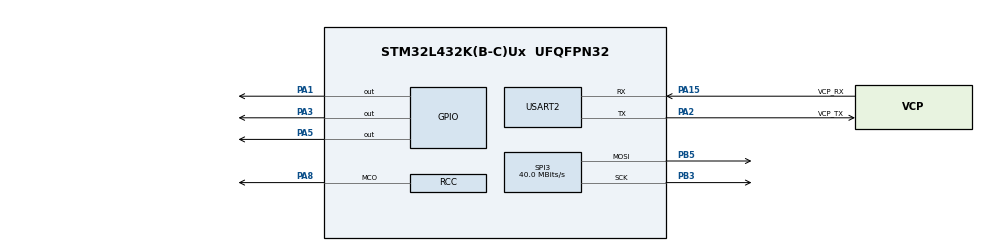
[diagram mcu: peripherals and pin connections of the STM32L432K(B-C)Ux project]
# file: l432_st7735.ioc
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Mcu.Family=STM32L4
Mcu.Name=STM32L432K(B-C)Ux
Mcu.Package=UFQFPN32
NVIC.PriorityGroup=NVIC_PRIORITYGROUP_4
PA0.GPIO_Label=MCO [High speed clock in]
PA0.Signal=RCC_CK_IN
PA1.Signal=GPIO_Output
PA13\ (JTMS-SWDIO).GPIO_Label=SWDIO
PA13\ (JTMS-SWDIO).Mode=Serial_Wire
PA13\ (JTMS-SWDIO).Signal=SYS_JTMS-SWDIO
PA14\ (JTCK-SWCLK).GPIO_Label=SWCLK
PA14\ (JTCK-SWCLK).Mode=Serial_Wire
PA14\ (JTCK-SWCLK).Signal=SYS_JTCK-SWCLK
PA15\ (JTDI).GPIO_Label=VCP_RX
PA15\ (JTDI).Mode=Asynchronous
PA15\ (JTDI).Signal=USART2_RX
PA2.GPIO_Label=VCP_TX
PA2.Mode=Asynchronous
PA2.Signal=USART2_TX
PA3.Signal=GPIO_Output
PA5.Signal=GPIO_Output
PA8.Mode=Clock-out
PA8.Signal=RCC_MCO
PB3\ (JTDO-TRACESWO).Mode=TX_Only_Simplex_Unidirect_Master
PB3\ (JTDO-TRACESWO).Signal=SPI3_SCK
PB5.Mode=TX_Only_Simplex_Unidirect_Master
PB5.Signal=SPI3_MOSI
PC14-OSC32_IN\ (PC14).Mode=LSE-External-Oscillator
PC14-OSC32_IN\ (PC14).Signal=RCC_OSC32_IN
PC15-OSC32_OUT\ (PC15).Mode=LSE-External-Oscillator
PC15-OSC32_OUT\ (PC15).Signal=RCC_OSC32_OUT
ProjectManager.HeapSize=0x200
ProjectManager.StackSize=0x400
ProjectManager.TargetToolchain=MDK-ARM V5.32
RCC.ADCFreq_Value=64000000
RCC.AHBFreq_Value=80000000
RCC.APB1Freq_Value=80000000
RCC.APB1TimFreq_Value=80000000
RCC.APB2Freq_Value=80000000
RCC.APB2TimFreq_Value=80000000
RCC.CortexFreq_Value=80000000
RCC.HCLKFreq_Value=80000000
RCC.HSE_VALUE=8000000
RCC.HSI16_VALUE=16000000
RCC.HSI48_VALUE=48000000
RCC.HSI_VALUE=16000000
RCC.MSI_VALUE=4000000
RCC.PLLMUL=RCC_PLLMUL_4
RCC.PLLN=10
RCC.PLLSourceVirtual=RCC_PLLSOURCE_HSI
RCC.PREFETCH_ENABLE=1
RCC.RCC_MCODiv=RCC_MCODIV_8
RCC.SYSCLKFreq_VALUE=80000000
RCC.SYSCLKSource=RCC_SYSCLKSOURCE_PLLCLK
RCC.USBFreq_Value=64000000
RCC.VCOOutputFreq_Value=160000000
SPI3.BaudRatePrescaler=SPI_BAUDRATEPRESCALER_2
SPI3.CalculateBaudRate=40.0 MBits/s
SPI3.DataSize=SPI_DATASIZE_8BIT
SPI3.Direction=SPI_DIRECTION_2LINES
SPI3.Mode=SPI_MODE_MASTER
SPI3.VirtualType=VM_MASTER
USART2.VirtualMode-Asynchronous=VM_ASYNC
board=NUCLEO-L432KC

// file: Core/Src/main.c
/* USER CODE BEGIN Header */
/**
  ******************************************************************************
  * @file           : main.c
  * @brief          : Main program body
  ******************************************************************************
  * @attention
  *
  * Copyright (c) 2021 STMicroelectronics.
  * All rights reserved.
  *
  * This software is licensed under terms that can be found in the LICENSE file
  * in the root directory of this software component.
  * If no LICENSE file comes with this software, it is provided AS-IS.
  *
  ******************************************************************************
  */
/* USER CODE END Header */
#include "main.h"

/* USER CODE BEGIN Includes */
#include "st7735.h"
#include "image.h"
/* USER CODE END Includes */

SPI_HandleTypeDef hspi3;

UART_HandleTypeDef huart2;

void SystemClock_Config(void);
static void MX_GPIO_Init(void);
static void MX_SPI3_Init(void);
static void MX_USART2_UART_Init(void);

int main(void)
{

  /* MCU Configuration--------------------------------------------------------*/

  /* Reset of all peripherals, Initializes the Flash interface and the Systick. */
  HAL_Init();

  /* Configure the system clock */
  SystemClock_Config();

  /* Initialize all configured peripherals */
  MX_GPIO_Init();
  MX_SPI3_Init();
  MX_USART2_UART_Init();
  /* USER CODE BEGIN 2 */

	//Change here

//  ST7735_init();
//
//	ST7735_Clr();
//
//	inhinhanh();

  /* USER CODE END 2 */

  /* Infinite loop */
  while (1)
  {

  }
}

void SystemClock_Config(void)
{
  RCC_OscInitTypeDef RCC_OscInitStruct = {0};
  RCC_ClkInitTypeDef RCC_ClkInitStruct = {0};

  /** Configure the main internal regulator output voltage
  */
  if (HAL_PWREx_ControlVoltageScaling(PWR_REGULATOR_VOLTAGE_SCALE1) != HAL_OK)
  {
    Error_Handler();
  }
  /** Initializes the RCC Oscillators according to the specified parameters
  * in the RCC_OscInitTypeDef structure.
  */
  RCC_OscInitStruct.OscillatorType = RCC_OSCILLATORTYPE_HSI;
  RCC_OscInitStruct.HSIState = RCC_HSI_ON;
  RCC_OscInitStruct.HSICalibrationValue = RCC_HSICALIBRATION_DEFAULT;
  RCC_OscInitStruct.PLL.PLLState = RCC_PLL_ON;
  RCC_OscInitStruct.PLL.PLLSource = RCC_PLLSOURCE_HSI;
  RCC_OscInitStruct.PLL.PLLM = 1;
  RCC_OscInitStruct.PLL.PLLN = 12;
  RCC_OscInitStruct.PLL.PLLP = RCC_PLLP_DIV7;
  RCC_OscInitStruct.PLL.PLLQ = RCC_PLLQ_DIV2;
  RCC_OscInitStruct.PLL.PLLR = RCC_PLLR_DIV8;
  if (HAL_RCC_OscConfig(&RCC_OscInitStruct) != HAL_OK)
  {
    Error_Handler();
  }
  /** Initializes the CPU, AHB and APB buses clocks
  */
  RCC_ClkInitStruct.ClockType = RCC_CLOCKTYPE_HCLK|RCC_CLOCKTYPE_SYSCLK
                              |RCC_CLOCKTYPE_PCLK1|RCC_CLOCKTYPE_PCLK2;
  RCC_ClkInitStruct.SYSCLKSource = RCC_SYSCLKSOURCE_PLLCLK;
  RCC_ClkInitStruct.AHBCLKDivider = RCC_SYSCLK_DIV1;
  RCC_ClkInitStruct.APB1CLKDivider = RCC_HCLK_DIV1;
  RCC_ClkInitStruct.APB2CLKDivider = RCC_HCLK_DIV1;

  if (HAL_RCC_ClockConfig(&RCC_ClkInitStruct, FLASH_LATENCY_1) != HAL_OK)
  {
    Error_Handler();
  }
}

static void MX_SPI3_Init(void)
{

  /* SPI3 parameter configuration*/
  hspi3.Instance = SPI3;
  hspi3.Init.Mode = SPI_MODE_MASTER;
  hspi3.Init.Direction = SPI_DIRECTION_2LINES;
  hspi3.Init.DataSize = SPI_DATASIZE_8BIT;
  hspi3.Init.CLKPolarity = SPI_POLARITY_LOW;
  hspi3.Init.CLKPhase = SPI_PHASE_1EDGE;
  hspi3.Init.NSS = SPI_NSS_SOFT;
  hspi3.Init.BaudRatePrescaler = SPI_BAUDRATEPRESCALER_8;
  hspi3.Init.FirstBit = SPI_FIRSTBIT_MSB;
  hspi3.Init.TIMode = SPI_TIMODE_DISABLE;
  hspi3.Init.CRCCalculation = SPI_CRCCALCULATION_DISABLE;
  hspi3.Init.CRCPolynomial = 7;
  hspi3.Init.CRCLength = SPI_CRC_LENGTH_DATASIZE;
  hspi3.Init.NSSPMode = SPI_NSS_PULSE_ENABLE;
  if (HAL_SPI_Init(&hspi3) != HAL_OK)
  {
    Error_Handler();
  }

}

static void MX_USART2_UART_Init(void)
{

  huart2.Instance = USART2;
  huart2.Init.BaudRate = 115200;
  huart2.Init.WordLength = UART_WORDLENGTH_8B;
  huart2.Init.StopBits = UART_STOPBITS_1;
  huart2.Init.Parity = UART_PARITY_NONE;
  huart2.Init.Mode = UART_MODE_TX_RX;
  huart2.Init.HwFlowCtl = UART_HWCONTROL_NONE;
  huart2.Init.OverSampling = UART_OVERSAMPLING_16;
  huart2.Init.OneBitSampling = UART_ONE_BIT_SAMPLE_DISABLE;
  huart2.AdvancedInit.AdvFeatureInit = UART_ADVFEATURE_NO_INIT;
  if (HAL_UART_Init(&huart2) != HAL_OK)
  {
    Error_Handler();
  }

}

static void MX_GPIO_Init(void)
{
  GPIO_InitTypeDef GPIO_InitStruct = {0};

  /* GPIO Ports Clock Enable */
  __HAL_RCC_GPIOC_CLK_ENABLE();
  __HAL_RCC_GPIOA_CLK_ENABLE();
  __HAL_RCC_GPIOB_CLK_ENABLE();

  /*Configure GPIO pin Output Level */
  HAL_GPIO_WritePin(GPIOA, GPIO_PIN_1|GPIO_PIN_3|GPIO_PIN_5, GPIO_PIN_RESET);

  /*Configure GPIO pins : PA1 PA3 PA5 */
  GPIO_InitStruct.Pin = GPIO_PIN_1|GPIO_PIN_3|GPIO_PIN_5;
  GPIO_InitStruct.Mode = GPIO_MODE_OUTPUT_PP;
  GPIO_InitStruct.Pull = GPIO_NOPULL;
  GPIO_InitStruct.Speed = GPIO_SPEED_FREQ_LOW;
  HAL_GPIO_Init(GPIOA, &GPIO_InitStruct);

}

void Error_Handler(void)
{
  __disable_irq();
  while (1)
  {
  }
}
